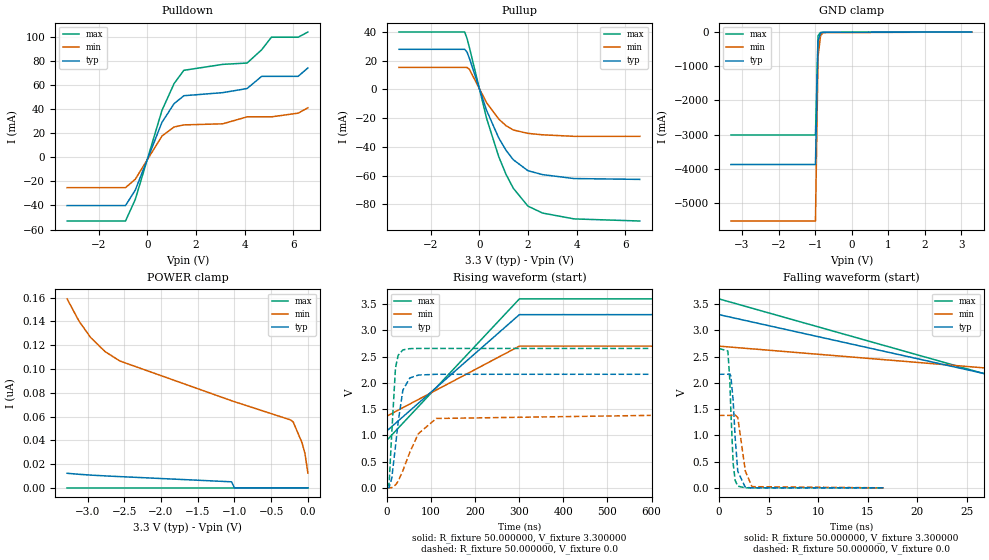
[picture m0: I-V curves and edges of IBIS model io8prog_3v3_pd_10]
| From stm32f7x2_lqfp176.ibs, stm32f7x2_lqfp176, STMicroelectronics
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|   Model io8prog_3v3_pd_10
[Model]  io8prog_3v3_pd_10
Model_type I/O
Polarity   Non-Inverting
Enable   Active-Low
Vinl =   0.990000V
Vinh =   2.310000V
Vmeas =  1.650000V
Cref =   100.000000nF
Rref =   1.000000k
Vref =   3.300000V
C_comp   2.665600pF   2.506300pF   2.859000pF
[Temperature Range]   25.000000   0.125000k   -40.000000
[Pullup Reference]   3.300000V   2.700000V   3.600000V
[Pulldown Reference]   0.0V   0.0V   0.0V
[POWER Clamp Reference]   3.300000V   2.700000V   3.600000V
[GND Clamp Reference]   0.0V   0.0V   0.0V
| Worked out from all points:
|   slope of the pulldown table from 0 to 0.495 V, typ, clamps not added: 20 ohm
|   slope of the pullup table from 0 to 0.495 V, typ, clamps not added: 21.7 ohm
|   GND clamp passes 1 mA (typ) near -0.57 V on its own axis
|   rising waveform, R_fixture 50.000000, V_fixture 3.300000: 20-80 % time 180ns typ, 180ns min, 180ns max; typ from 1.09 V to 3.3 V
|   rising waveform, R_fixture 50.000000, V_fixture 0.0: 20-80 % time 18.3ns typ, 43.3ns min, 9.76ns max; typ from 0 V to 2.16 V
|   falling waveform, R_fixture 50.000000, V_fixture 3.300000: 20-80 % time 31.6ns typ, 63.2ns min, 30.3ns max; typ from 3.3 V to 1.09 V
|   falling waveform, R_fixture 50.000000, V_fixture 0.0: 20-80 % time 421ps typ, 610ps min, 335ps max; typ from 2.16 V to 0 V
[Pulldown]
|Voltage   I(typ)   I(min)   I(max)
-3.3V     -40.11mA   -25.24mA   -52.93mA
-900mV    -40.11mA   -25.24mA   -52.93mA
-500mV    -27.39mA   -18.32mA   -35.21mA
600mV     29.01mA    17.61mA    38.88mA
1.1V      44.56mA    25.16mA    61.26mA
1.5V      51.11mA    26.89mA    72.21mA
3.1V      53.67mA    27.79mA    77.15mA
4.1V      57.1mA     33.57mA    78.25mA
4.7V      67.22mA    33.57mA    89.26mA
5.1V      67.22mA    33.57mA    99.69mA
6.2V      67.22mA    36.63mA    99.69mA
6.6V      74.18mA    41.08mA    104mA
[Pullup]
|Voltage   I(typ)   I(min)   I(max)
-3.3V     27.94mA    15.3mA     39.98mA
-600mV    27.94mA    15.3mA     39.98mA
-500mV    25.89mA    15.3mA     35.29mA
-400mV    21.3mA     13.82mA    28.75mA
300mV     -14.62mA   -9.248mA   -20.15mA
800mV     -33.8mA    -20.67mA   -46.89mA
1.1V      -42.41mA   -25.27mA   -59.19mA
1.4V      -49.01mA   -28.29mA   -68.91mA
2V        -56.64mA   -30.64mA   -81.32mA
2.6V      -59.37mA   -31.63mA   -86.15mA
3.9V      -62.11mA   -32.7mA    -90.24mA
6.6V      -62.7mA    -32.7mA    -91.7mA
[GND_clamp]
|Voltage   I(typ)   I(min)   I(max)
-3.3V     -3.872A    -5.523A    -3.009A
-990mV    -3.872A    -5.523A    -3.009A
-920mV    -262.2mA   -719.6mA   -104.3mA
-850mV    -25.2mA    -101mA     -13.09mA
-780mV    -6.971mA   -18.01mA   -7.205mA
3.28V     81.28uA    57.88uA    93.99uA
[POWER_clamp]
|Voltage   I(typ)   I(min)   I(max)
-3.28V    12.27nA    159nA      0A
-3.12V    11.41nA    140.5nA    0A
-2.96V    10.73nA    126.5nA    0A
-2.76V    10.05nA    114.5nA    0A
-2.56V    9.455nA    106.7nA    0A
-1.04V    5.085nA    73.31nA    0A
-1V       0A         72.48nA    0A
-240mV    0A         57.24nA    0A
-200mV    0A         55.42nA    0A
-80mV     0A         37.96nA    0A
-40mV     0A         28.96nA    0A
0V        0A         12.44nA    0A
[Ramp]
| variable   typ   min   max
dV/dt_r  1.29804/18.26314n   0.82812/43.29273n   1.59294/9.74051n
dV/dt_f  1.32738/17.43925n   0.79914/35.61971n   1.61393/10.83131n
R_load = 50.000000
[Rising Waveform]
R_fixture= 50.000000
V_fixture= 3.300000
V_fixture_min= 2.700000
V_fixture_max= 3.600000
|time   V(typ)   V(min)   V(max)
0s        1.087V     1.367V     909mV
300.3ns   3.299V     2.699V     3.599V
600.6ns   3.299V     2.699V     3.599V
29.73us   3.299V     2.699V     3.599V
[Rising Waveform]
R_fixture= 50.000000
V_fixture= 0.0
V_fixture_min= 0.0
V_fixture_max= 0.0
|time   V(typ)   V(min)   V(max)
0s        3.79nV     209.7nV    2.596nV
4.805ns   3.881mV    -152.2uV   84.74mV
10.81ns   183mV      2.956mV    1.04V
19.22ns   791.6mV    54.52mV    2.282V
25.23ns   1.249V     124.9mV    2.523V
36.04ns   1.861V     326.7mV    2.627V
51.65ns   2.092V     673.4mV    2.651V
70.87ns   2.147V     1.029V     2.655V
111.7ns   2.163V     1.321V     2.655V
598.2ns   2.163V     1.38V      2.655V
[Falling Waveform]
R_fixture= 50.000000
V_fixture= 3.300000
V_fixture_min= 2.700000
V_fixture_max= 3.600000
|time   V(typ)   V(min)   V(max)
0s        3.299V     2.699V     3.599V
50.05ns   1.198V     1.923V     931.7mV
100.1ns   1.095V     1.445V     909.9mV
150.2ns   1.087V     1.384V     909.1mV
200.2ns   1.087V     1.371V     909mV
4.955us   1.087V     1.367V     909mV
[Falling Waveform]
R_fixture= 50.000000
V_fixture= 0.0
V_fixture_min= 0.0
V_fixture_max= 0.0
|time   V(typ)   V(min)   V(max)
0s        2.163V     1.38V      2.655V
900.9ps   2.164V     1.38V      2.607V
1.101ns   2.17V      1.38V      2.046V
1.201ns   2.13V      1.38V      1.486V
1.435ns   1.667V     1.381V     467.4mV
1.635ns   963mV      1.388V     144.5mV
1.902ns   313.9mV    1.339V     32.22mV
2.669ns   7.473mV    316mV      795.6uV
3.337ns   477.1uV    22.75mV    464.6uV
16.62ns   3.79nV     209.7nV    2.596nV
